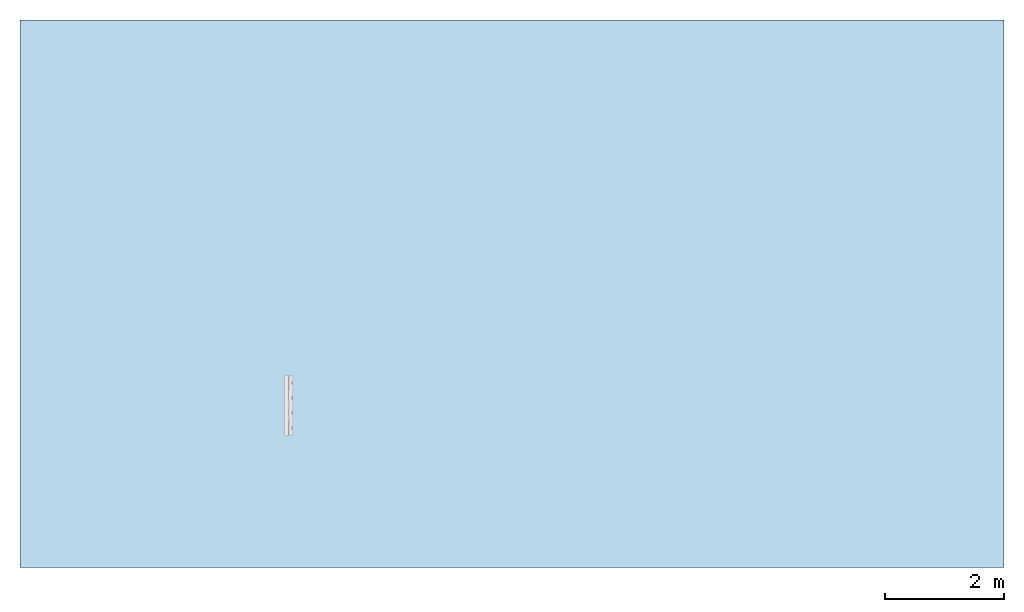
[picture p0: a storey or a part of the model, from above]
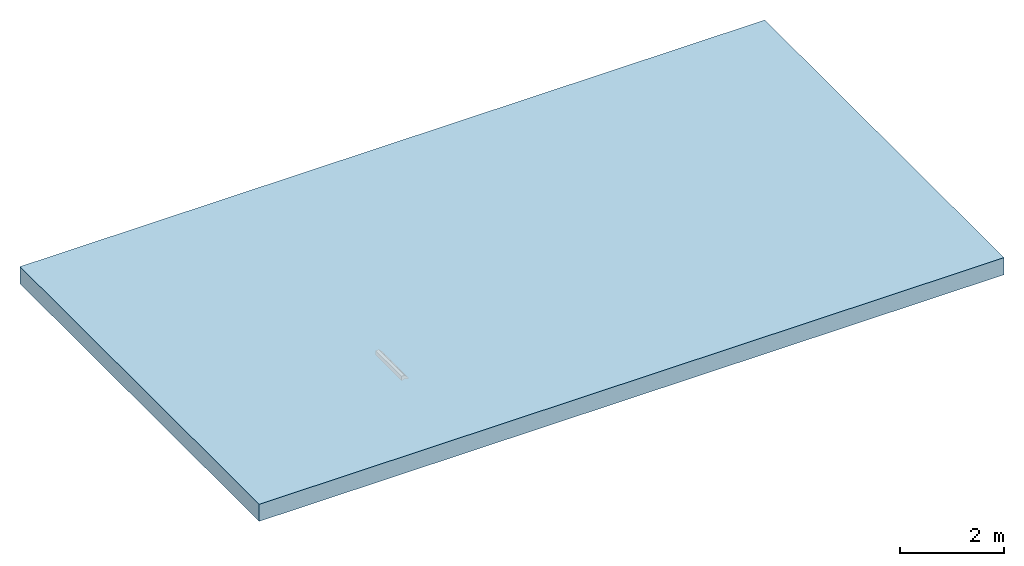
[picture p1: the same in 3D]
Properties of the parts of a building model (IFC2X3)

# File
Description: ViewDefinition [CoordinationView]
File name: 7930 - KDSP280 Channel - 1000mm LG.ifc
Time: 2013-09-02T12:30:16
Written by: Autodesk Revit 2013
Made in: 20120221_2030(x64)

# IfcProject, Project Number
LongName: Project Name; Phase: Project Status

# IfcSite, Default
RefLatitude: 42, 21, 30, 344238; RefLongitude: -71, -3, -35, -194702; RefElevation: 0 mm

# IfcBuilding
Pset_BuildingCommon - NumberOfStoreys: 1
Other - Project Address: ## Street City, State Zip; Project Issue Date: Issue Date; Project Name: Project Name; Project Number: Project Number; Project Status: Project Status; Client Name: Owner

# IfcBuildingStorey, Level 1
LongName: Level 1; Elevation: 0 mm
Constraints - Elevation Base: 0; Elevation: 0 mm
Graphics - Symbol at End 2 Default: yes; Symbol at End 1 Default: no; Symbol: M_Level Head - Circle: M_Level Head - Circle; Line Weight: 1; Color: 0; Line Pattern: Center
Identity Data - Building Story: yes; Structural: no; Name: Level 1
Dimensions - Computation Height: 0 mm

# IfcBuildingElementProxy: 7930 - KDSP280 Channel - 1000mm LG, Civil-Drainage-Channel-ACO-KerbDrain-SP280:7930 - KDSP280 Channel - 1000mm LG:7930 - KDSP280 Channel - 1000mm LG:311063
In: Level 1
Material: ACO Polymer Concrete.
Phasing - Phase Created: New Construction
Dimensions - Volume: 23207236 mm3; Void Width: 150 mm; Access hole: 2 mm; AccessDepth: 0 mm; Endcap void: 205 mm; Void Length: 1000 mm; Void Depth: -180 mm
Constraints - Moves With Nearby Elements: no; Level: Level: Level 1
Pset_BuildingElementProxyCommon - Reference: 7930 - KDSP280 Channel - 1000mm LG
Construction - Centre Stone: no; Closing end cap: no; SP280 - 1000: yes; RH transition unit: no; perforated centre stone: no; LH drop kerb: no; SP280-500: no; RH drop kerb: no; RH inlet/outlet end cap: no; Access Unit: no; LH inlet/outlet end cap: no; LH transition unit: no
Identity Data - e-mail Sales: customersupport@aco.co.uk; Maintenance guidelines: http://www.aco.co.uk/download.php?id=120; Assembly Code: D2040; e-mail Technical: technical@aco.co.uk; Model: ACO KerbDrain SP280; Fax: +44 (0)1462 815895; Installation guidelines: http://www.aco.co.uk/download.php?id=120; Assembly Description: Rain Water Drainage; Product Page URL: http://www.aco.co.uk/product_detail.php?id=3; Cost: 0; OmniClass Title: Rainwater Removal; Price: POA - contact ACO; OmniClass Number: 23.70.50.24; Model Description: Combined kerb and drainage system; Address: ACO Business Park, Hitchin Road, Shefford, Bedfordshire, United Kingdom SG17 5TE; Product brochure: http://www.aco.co.uk/download.php?id=120; URL: www.aco.co.uk; Manufacturer: ACO Technologies plc - ACO Water Management Division; Telephone: +44 (0)1462 816666; Type Comments: ACO KerbDrain SP280 splayed kerb unit 1000mm long; Product Code: 7930
Other - Revision: 1; CreatedBy: www.aco.co.uk
Data - Drainage Slot Intake area: 14592mm²/m; Hydraulic Performance: http://www.aco.co.uk/download.php?id=120; Concrete Surround Volume - Load Class A 15 - D 400 - Grass or Asphalt Pavement: 0.12m³/m; ACO Hydraulic Design Software: http://www.acodesign.co.uk; Drainage Slot Width: 50mm; Product Standard: BS EN 1433:2002, CE marked, Kitemarked; Concrete Surround Volume - Load Class A 15 - D 400 - Concrete Pavement: 0.14m³/m; Channel C.S.A: 0.02m²; Load Class: A 15 - D 400 A 15 - D 400; Installation - Concrete Grade: Refer to brochure; Connection Pipe O.D: N/A; Product Dimensions: 1000mm x 150mm x 280mm (LxWxH); Invert Depth: 255mm; Product Weight: 44.9 Kg
General - SerialNumber: 0.000000; TagNumber: 0.000000
Materials and Finishes - End Cap Material: N/A; Access Cover/Frame Finish: N/A; Access Cover/Frame Material: N/A; Connection Pipe Material Colour: N/A; Connection Pipe Material: N/A; End Cap Colour: N/A; Channel Material: Vienite® Synthetic Resin Concrete; Access Cover/Frame Colour: N/A; Channel Colour: Grey
Green Building Properties - Channel Recyclable: Fully recyclable; Channel Recycled Material Content: 20% minimum; End Cap Recycled Material Content: N/A; Access Cover/Frame Recyclable: N/A; End Cap Recyclable: N/A; Access Cover/Frame Recycled Material Content: N/A

# IfcOpeningElement: Recess
In: Level 1
Dimensions - Perimeter: 51360 mm; Thickness: 400 mm; Volume: 60561000000 mm3; Area: 151470000 mm2
Phasing - Phase Created: New Construction
Constraints - Related to Mass: no; Level: Level: Level 1; Room Bounding: yes; Height Offset From Level: 0 mm
Structural - Structural: no; Enable Analytical Model: no
Analytical Properties - Roughness: 1; Absorptance: 0.1
Construction - Default Thickness: 400 mm; Function: 0
Graphics - Coarse Scale Fill Color: 0
Materials and Finishes - Structural Material: Plant

# IfcSlab: Floor:Generic Floor - 400mm, Floor:Generic Floor - 400mm:193825
In: Level 1
PredefinedType: FLOOR; Material: Plant 400 mm
Dimensions - Perimeter: 51360 mm; Thickness: 400 mm; Volume: 60561000000 mm3; Area: 151470000 mm2
Phasing - Phase Created: New Construction
Constraints - Related to Mass: no; Level: Level: Level 1; Room Bounding: yes; Height Offset From Level: 0 mm
Structural - Structural: no; Enable Analytical Model: no
Pset_SlabCommon - Reference: Generic Floor - 400mm; IsExternal: no; LoadBearing: yes
Analytical Properties - Roughness: 1; Absorptance: 0.1
Construction - Default Thickness: 400 mm; Function: 0
Graphics - Coarse Scale Fill Color: 0
Materials and Finishes - Structural Material: Plant
